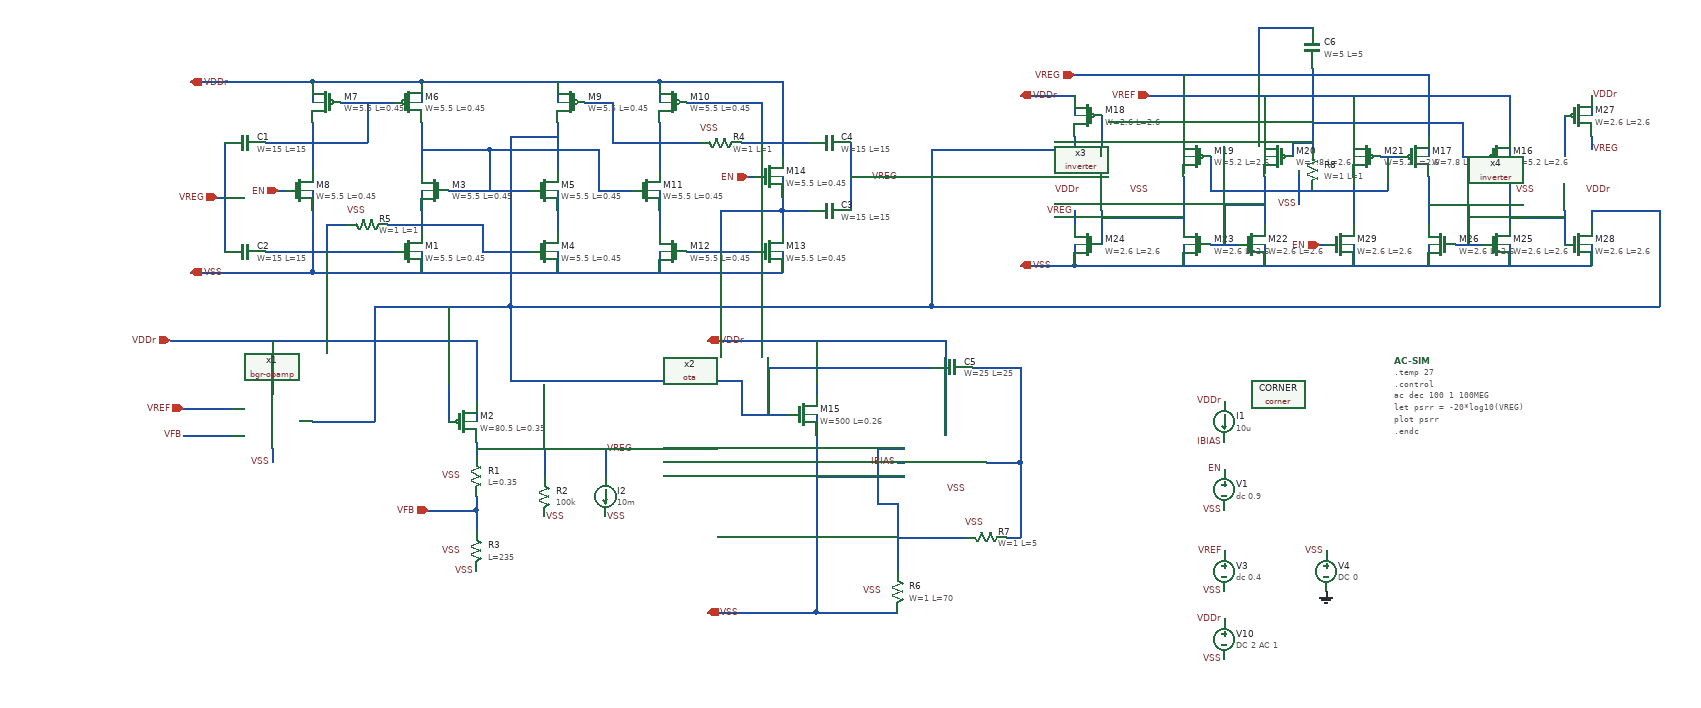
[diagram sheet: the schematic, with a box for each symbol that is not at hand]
v {xschem version=3.4.7 file_version=1.2}
G {}
K {}
V {}
S {}
E {}
N 230 -500 650 -500 {lab=VDDr}
N 650 -350 650 -330 {lab=VREG}
N 650 -440 650 -410 {lab=VDDr}
N 650 -460 650 -440 {lab=VDDr}
N 650 -410 650 -380 {lab=VDDr}
N 780 -340 840 -340 {lab=VREG}
N 650 -340 780 -340 {lab=VREG}
N 840 -340 840 -320 {lab=VREG}
N 840 -320 840 -300 {lab=VREG}
N 650 -250 650 -230 {lab=VFB}
N 580 -250 650 -250 {lab=VFB}
N 650 -270 650 -250 {lab=VFB}
N 650 -230 650 -220 {lab=VFB}
N 650 -500 650 -460 {lab=VDDr}
N 350 -460 350 -420 {lab=VDDr}
N 200 -500 230 -500 {lab=VDDr}
N 220 -400 290 -400 {lab=VREF}
N 220 -360 290 -360 {lab=VFB}
N 350 -340 350 -320 {lab=VSS}
N 350 -500 350 -460 {lab=VDDr}
N 750 -340 750 -300 {lab=VREG}
N 410 -880 570 -880 {lab=VDDr}
N 570 -880 570 -850 {lab=VDDr}
N 410 -880 410 -850 {lab=VDDr}
N 450 -850 530 -850 {lab=#net1}
N 570 -820 570 -750 {lab=#net2}
N 610 -720 730 -720 {lab=#net2}
N 570 -690 570 -660 {lab=#net3}
N 770 -690 770 -660 {lab=#net4}
N 660 -630 730 -630 {lab=#net3}
N 660 -670 660 -630 {lab=#net3}
N 570 -670 660 -670 {lab=#net3}
N 770 -630 770 -600 {lab=VSS}
N 570 -630 570 -600 {lab=VSS}
N 570 -780 670 -780 {lab=#net2}
N 670 -780 670 -720 {lab=#net2}
N 410 -820 410 -750 {lab=#net1}
N 410 -720 410 -690 {lab=VSS}
N 340 -630 530 -630 {lab=#net5}
N 340 -790 410 -790 {lab=#net1}
N 490 -850 490 -790 {lab=#net1}
N 410 -790 490 -790 {lab=#net1}
N 410 -690 410 -610 {lab=VSS}
N 410 -610 410 -600 {lab=VSS}
N 280 -790 280 -630 {lab=VREG}
N 770 -820 770 -750 {lab=#net6}
N 570 -720 570 -690 {lab=#net3}
N 770 -720 770 -690 {lab=#net4}
N 670 -780 830 -780 {lab=#net2}
N 830 -780 830 -720 {lab=#net2}
N 830 -720 880 -720 {lab=#net2}
N 920 -820 920 -750 {lab=#net7}
N 920 -880 920 -850 {lab=VDDr}
N 770 -880 770 -850 {lab=VDDr}
N 570 -880 920 -880 {lab=VDDr}
N 920 -720 920 -690 {lab=#net8}
N 960 -630 1060 -630 {lab=#net9}
N 920 -690 920 -660 {lab=#net8}
N 920 -630 920 -600 {lab=VSS}
N 1100 -630 1100 -600 {lab=VSS}
N 810 -850 850 -850 {lab=#net7}
N 850 -850 850 -790 {lab=#net7}
N 850 -790 920 -790 {lab=#net7}
N 930 -790 980 -790 {lab=#net7}
N 920 -790 930 -790 {lab=#net7}
N 920 -880 1100 -880 {lab=VDDr}
N 1010 -690 1010 -630 {lab=#net9}
N 1010 -690 1100 -690 {lab=#net9}
N 1100 -690 1140 -690 {lab=#net9}
N 1040 -790 1140 -790 {lab=VDDr}
N 1200 -790 1200 -690 {lab=VREG}
N 410 -600 1100 -600 {lab=VSS}
N 230 -600 410 -600 {lab=VSS}
N 230 -880 410 -880 {lab=VDDr}
N 960 -850 1070 -850 {lab=VDDr}
N 1070 -850 1070 -790 {lab=VDDr}
N 360 -720 370 -720 {lab=EN}
N 430 -670 460 -670 {lab=#net5}
N 430 -670 430 -630 {lab=#net5}
N 520 -670 570 -670 {lab=#net3}
N 270 -710 280 -710 {lab=VREG}
N 1200 -740 1210 -740 {lab=VREG}
N 1210 -740 1230 -740 {lab=VREG}
N 730 -800 770 -800 {lab=#net6}
N 1100 -740 1100 -710 {lab=#net9}
N 1050 -740 1060 -740 {lab=EN}
N 1100 -710 1100 -690 {lab=#net9}
N 1100 -690 1100 -660 {lab=#net9}
N 1100 -790 1100 -770 {lab=VDDr}
N 1100 -880 1100 -790 {lab=VDDr}
N 610 -550 610 -380 {lab=#net6}
N 500 -550 700 -550 {lab=#net6}
N 700 -800 700 -550 {lab=#net6}
N 700 -800 730 -800 {lab=#net6}
N 410 -380 500 -380 {lab=#net6}
N 500 -550 500 -380 {lab=#net6}
N 1270 -210 1370 -210 {lab=#net10}
N 1150 -360 1150 -100 {lab=VSS}
N 1150 -100 1270 -100 {lab=VSS}
N 1410 -320 1450 -320 {lab=#net11}
N 1450 -320 1450 -210 {lab=#net11}
N 1430 -210 1450 -210 {lab=#net11}
N 1380 -460 1450 -460 {lab=#net11}
N 1450 -460 1450 -320 {lab=#net11}
N 1040 -390 1110 -390 {lab=#net6}
N 1080 -460 1320 -460 {lab=#net6}
N 1080 -460 1080 -390 {lab=#net6}
N 1150 -500 1150 -420 {lab=VDDr}
N 1150 -390 1150 -360 {lab=VSS}
N 990 -500 1310 -500 {lab=VDDr}
N 990 -100 1150 -100 {lab=VSS}
N 1310 -500 1340 -500 {lab=VDDr}
N 1340 -500 1340 -360 {lab=VDDr}
N 1400 -320 1410 -320 {lab=#net11}
N 1270 -320 1280 -320 {lab=IBIAS}
N 1040 -440 1040 -390 {lab=#net6}
N 700 -550 700 -440 {lab=#net6}
N 700 -440 1040 -440 {lab=#net6}
N 1810 -860 1810 -800 {lab=VREF}
N 1940 -860 1940 -800 {lab=VREF}
N 2170 -860 2170 -800 {lab=VREF}
N 1780 -860 2170 -860 {lab=VREF}
N 1690 -890 1690 -800 {lab=VREG}
N 2050 -890 2050 -800 {lab=VREG}
N 1530 -890 2050 -890 {lab=VREG}
N 1690 -740 1690 -670 {lab=#net12}
N 1810 -740 1810 -670 {lab=#net13}
N 1730 -640 1770 -640 {lab=#net13}
N 1750 -700 1750 -640 {lab=#net13}
N 1750 -700 1810 -700 {lab=#net13}
N 1980 -770 2010 -770 {lab=#net14}
N 2090 -640 2130 -640 {lab=#net15}
N 2050 -740 2050 -670 {lab=#net15}
N 2170 -740 2170 -670 {lab=#net16}
N 2050 -700 2110 -700 {lab=#net15}
N 2110 -700 2110 -640 {lab=#net15}
N 1540 -610 2290 -610 {lab=VSS}
N 1530 -610 1540 -610 {lab=VSS}
N 1570 -690 1570 -670 {lab=#net12}
N 1570 -680 1690 -680 {lab=#net12}
N 1570 -780 1570 -770 {lab=#net17}
N 1530 -860 1530 -830 {lab=VDDr}
N 1530 -640 1530 -610 {lab=VSS}
N 1570 -670 1570 -640 {lab=#net12}
N 1530 -800 1530 -780 {lab=#net6}
N 1530 -690 1530 -670 {lab=VREG}
N 1570 -830 1570 -780 {lab=#net17}
N 1640 -860 1780 -860 {lab=VREF}
N 2250 -690 2250 -670 {lab=#net16}
N 2250 -780 2250 -770 {lab=#net18}
N 2290 -860 2290 -830 {lab=VDDr}
N 2290 -640 2290 -610 {lab=VSS}
N 2250 -670 2250 -640 {lab=#net16}
N 2290 -800 2290 -780 {lab=VREG}
N 2290 -690 2290 -670 {lab=#net6}
N 2250 -830 2250 -780 {lab=#net18}
N 2170 -680 2250 -680 {lab=#net16}
N 1450 -860 1530 -860 {lab=VDDr}
N 1450 -610 1530 -610 {lab=VSS}
N 1690 -800 1690 -770 {lab=VREG}
N 1810 -800 1810 -770 {lab=VREF}
N 1940 -800 1940 -770 {lab=VREF}
N 2050 -800 2050 -770 {lab=VREG}
N 2170 -800 2170 -770 {lab=VREF}
N 1810 -640 1810 -610 {lab=VSS}
N 1690 -640 1690 -610 {lab=VSS}
N 2170 -640 2170 -610 {lab=VSS}
N 1940 -740 1940 -670 {lab=#net14}
N 1990 -770 1990 -720 {lab=#net14}
N 1940 -720 1990 -720 {lab=#net14}
N 1730 -770 1730 -720 {lab=#net14}
N 1730 -720 1940 -720 {lab=#net14}
N 1880 -840 1880 -780 {lab=#net19}
N 1850 -790 1850 -770 {lab=#net19}
N 1850 -790 1880 -790 {lab=#net19}
N 2100 -770 2130 -770 {lab=#net19}
N 2100 -820 2100 -770 {lab=#net19}
N 1880 -820 2100 -820 {lab=#net19}
N 1880 -900 1880 -840 {lab=#net19}
N 1800 -960 1880 -960 {lab=VREG}
N 1800 -960 1800 -890 {lab=VREG}
N 1860 -750 1860 -700 {lab=VSS}
N 1940 -640 1940 -610 {lab=VSS}
N 2050 -640 2050 -610 {lab=VSS}
N 1890 -640 1900 -640 {lab=EN}
N 1320 -780 1530 -780 {lab=#net6}
N 1320 -780 1320 -550 {lab=#net6}
N 700 -550 1320 -550 {lab=#net6}
N 1320 -550 2390 -550 {lab=#net6}
N 2390 -690 2390 -550 {lab=#net6}
N 2290 -690 2390 -690 {lab=#net6}
N 1240 -340 1280 -340 {lab=#net10}
N 1240 -340 1240 -260 {lab=#net10}
N 1240 -260 1270 -260 {lab=#net10}
N 1270 -260 1270 -160 {lab=#net10}
N 1150 -300 1280 -300 {lab=VSS}
C {code_shown.sym} 2000 -470 0 0 {name="AC-SIM" only_toplevel=false value="

.temp 27
.control

ac dec 100 1 100MEG
let psrr = -20*log10(VREG)


plot psrr

.endc
"}
C {sky130_fd_pr/pfet_01v8.sym} 630 -380 0 0 {name=M2
W=80.5
L=0.35
nf=40
mult=100
ad="'int((nf+1)/2) * W/nf * 0.29'" 
pd="'2*int((nf+1)/2) * (W/nf + 0.29)'"
as="'int((nf+2)/2) * W/nf * 0.29'" 
ps="'2*int((nf+2)/2) * (W/nf + 0.29)'"
nrd="'0.29 / W'" nrs="'0.29 / W'"
sa=0 sb=0 sd=0
model=pfet_01v8
spiceprefix=X
}
C {lab_pin.sym} 630 -300 0 0 {name=p13 sig_type=std_logic lab=VSS}
C {lab_pin.sym} 220 -360 0 0 {name=p16 lab=VFB}
C {lab_pin.sym} 350 -320 0 0 {name=p18 sig_type=std_logic lab=VSS}
C {ipin.sym} 200 -500 0 0 {name=p25 lab=VDDr}
C {ipin.sym} 220 -400 0 0 {name=p28 lab=VREF}
C {isource.sym} 840 -270 0 0 {name=I2 value="10m"}
C {lab_pin.sym} 840 -240 0 1 {name=p29 sig_type=std_logic lab=VSS}
C {lab_pin.sym} 840 -340 0 1 {name=p32 sig_type=std_logic lab=VREG}
C {ipin.sym} 580 -250 0 0 {name=p11 lab=VFB}
C {lab_pin.sym} 630 -190 0 0 {name=p1 sig_type=std_logic lab=VSS}
C {lab_pin.sym} 650 -160 0 0 {name=p2 sig_type=std_logic lab=VSS}
C {sky130_fd_pr/res_high_po_0p35.sym} 650 -190 0 0 {name=R3
L=235
model=res_high_po_0p35
spiceprefix=X
mult=1}
C {sky130_fd_pr/res_high_po_2p85.sym} 650 -300 0 0 {name=R1
L=0.35
model=res_high_po_2p85
spiceprefix=X
mult=1}
C {vsource.sym} 1750 -160 0 0 {name=V3 value="dc 0.4" savecurrent=false}
C {lab_pin.sym} 1750 -130 0 0 {name=p9 sig_type=std_logic lab=VSS}
C {lab_pin.sym} 1750 -190 0 0 {name=p12 sig_type=std_logic lab=VREF}
C {vsource.sym} 1900 -160 0 0 {name=V4 value="DC 0" savecurrent=false}
C {gnd.sym} 1900 -130 0 0 {name=l2 lab=GND}
C {lab_pin.sym} 1900 -190 0 0 {name=p14 sig_type=std_logic lab=VSS}
C {sky130_fd_pr/corner.sym} 1830 -420 0 0 {name=CORNER only_toplevel=true corner=ss}
C {vsource.sym} 1750 -60 0 0 {name=V10 value="DC 2 AC 1" savecurrent=false}
C {lab_pin.sym} 1750 -30 0 0 {name=p30 sig_type=std_logic lab=VSS}
C {lab_pin.sym} 1750 -90 0 0 {name=p31 sig_type=std_logic lab=VDDr}
C {res.sym} 750 -270 0 0 {name=R2
value=100k
footprint=1206
device=resistor
m=1}
C {lab_pin.sym} 750 -240 0 1 {name=p4 sig_type=std_logic lab=VSS}
C {afe-icdec-teknofest-2026/bandgap/bgr-opamp/bgr-opamp.sym} 40 -220 0 0 {name=x1}
C {sky130_fd_pr/nfet_01v8.sym} 550 -630 0 0 {name=M1
W=5.5
L=0.45
nf=1 
mult=1
ad="'int((nf+1)/2) * W/nf * 0.29'" 
pd="'2*int((nf+1)/2) * (W/nf + 0.29)'"
as="'int((nf+2)/2) * W/nf * 0.29'" 
ps="'2*int((nf+2)/2) * (W/nf + 0.29)'"
nrd="'0.29 / W'" nrs="'0.29 / W'"
sa=0 sb=0 sd=0
model=nfet_01v8
spiceprefix=X
}
C {sky130_fd_pr/nfet_01v8.sym} 590 -720 0 1 {name=M3
W=5.5
L=0.45
nf=1 
mult=1
ad="'int((nf+1)/2) * W/nf * 0.29'" 
pd="'2*int((nf+1)/2) * (W/nf + 0.29)'"
as="'int((nf+2)/2) * W/nf * 0.29'" 
ps="'2*int((nf+2)/2) * (W/nf + 0.29)'"
nrd="'0.29 / W'" nrs="'0.29 / W'"
sa=0 sb=0 sd=0
model=nfet_01v8
spiceprefix=X
}
C {sky130_fd_pr/nfet_01v8.sym} 750 -630 0 0 {name=M4
W=5.5
L=0.45
nf=1 
mult=1
ad="'int((nf+1)/2) * W/nf * 0.29'" 
pd="'2*int((nf+1)/2) * (W/nf + 0.29)'"
as="'int((nf+2)/2) * W/nf * 0.29'" 
ps="'2*int((nf+2)/2) * (W/nf + 0.29)'"
nrd="'0.29 / W'" nrs="'0.29 / W'"
sa=0 sb=0 sd=0
model=nfet_01v8
spiceprefix=X
}
C {sky130_fd_pr/nfet_01v8.sym} 750 -720 0 0 {name=M5
W=5.5
L=0.45
nf=1 
mult=1
ad="'int((nf+1)/2) * W/nf * 0.29'" 
pd="'2*int((nf+1)/2) * (W/nf + 0.29)'"
as="'int((nf+2)/2) * W/nf * 0.29'" 
ps="'2*int((nf+2)/2) * (W/nf + 0.29)'"
nrd="'0.29 / W'" nrs="'0.29 / W'"
sa=0 sb=0 sd=0
model=nfet_01v8
spiceprefix=X
}
C {sky130_fd_pr/pfet_01v8.sym} 550 -850 0 0 {name=M6
W=5.5
L=0.45
nf=1
mult=1
ad="'int((nf+1)/2) * W/nf * 0.29'" 
pd="'2*int((nf+1)/2) * (W/nf + 0.29)'"
as="'int((nf+2)/2) * W/nf * 0.29'" 
ps="'2*int((nf+2)/2) * (W/nf + 0.29)'"
nrd="'0.29 / W'" nrs="'0.29 / W'"
sa=0 sb=0 sd=0
model=pfet_01v8
spiceprefix=X
}
C {sky130_fd_pr/pfet_01v8.sym} 430 -850 0 1 {name=M7
W=5.5
L=0.45
nf=1
mult=1
ad="'int((nf+1)/2) * W/nf * 0.29'" 
pd="'2*int((nf+1)/2) * (W/nf + 0.29)'"
as="'int((nf+2)/2) * W/nf * 0.29'" 
ps="'2*int((nf+2)/2) * (W/nf + 0.29)'"
nrd="'0.29 / W'" nrs="'0.29 / W'"
sa=0 sb=0 sd=0
model=pfet_01v8
spiceprefix=X
}
C {sky130_fd_pr/nfet_01v8.sym} 390 -720 0 0 {name=M8
W=5.5
L=0.45
nf=1 
mult=1
ad="'int((nf+1)/2) * W/nf * 0.29'" 
pd="'2*int((nf+1)/2) * (W/nf + 0.29)'"
as="'int((nf+2)/2) * W/nf * 0.29'" 
ps="'2*int((nf+2)/2) * (W/nf + 0.29)'"
nrd="'0.29 / W'" nrs="'0.29 / W'"
sa=0 sb=0 sd=0
model=nfet_01v8
spiceprefix=X
}
C {sky130_fd_pr/cap_mim_m3_1.sym} 310 -790 3 0 {name=C1 model=cap_mim_m3_1 W=15 L=15 MF=4 spiceprefix=X}
C {sky130_fd_pr/cap_mim_m3_1.sym} 310 -630 3 0 {name=C2 model=cap_mim_m3_1 W=15 L=15 MF=4 spiceprefix=X}
C {sky130_fd_pr/pfet_01v8.sym} 790 -850 0 1 {name=M9
W=5.5
L=0.45
nf=1
mult=1
ad="'int((nf+1)/2) * W/nf * 0.29'" 
pd="'2*int((nf+1)/2) * (W/nf + 0.29)'"
as="'int((nf+2)/2) * W/nf * 0.29'" 
ps="'2*int((nf+2)/2) * (W/nf + 0.29)'"
nrd="'0.29 / W'" nrs="'0.29 / W'"
sa=0 sb=0 sd=0
model=pfet_01v8
spiceprefix=X
}
C {sky130_fd_pr/pfet_01v8.sym} 940 -850 0 1 {name=M10
W=5.5
L=0.45
nf=1
mult=1
ad="'int((nf+1)/2) * W/nf * 0.29'" 
pd="'2*int((nf+1)/2) * (W/nf + 0.29)'"
as="'int((nf+2)/2) * W/nf * 0.29'" 
ps="'2*int((nf+2)/2) * (W/nf + 0.29)'"
nrd="'0.29 / W'" nrs="'0.29 / W'"
sa=0 sb=0 sd=0
model=pfet_01v8
spiceprefix=X
}
C {sky130_fd_pr/nfet_01v8.sym} 900 -720 0 0 {name=M11
W=5.5
L=0.45
nf=1 
mult=1
ad="'int((nf+1)/2) * W/nf * 0.29'" 
pd="'2*int((nf+1)/2) * (W/nf + 0.29)'"
as="'int((nf+2)/2) * W/nf * 0.29'" 
ps="'2*int((nf+2)/2) * (W/nf + 0.29)'"
nrd="'0.29 / W'" nrs="'0.29 / W'"
sa=0 sb=0 sd=0
model=nfet_01v8
spiceprefix=X
}
C {sky130_fd_pr/nfet_01v8.sym} 940 -630 0 1 {name=M12
W=5.5
L=0.45
nf=1 
mult=1
ad="'int((nf+1)/2) * W/nf * 0.29'" 
pd="'2*int((nf+1)/2) * (W/nf + 0.29)'"
as="'int((nf+2)/2) * W/nf * 0.29'" 
ps="'2*int((nf+2)/2) * (W/nf + 0.29)'"
nrd="'0.29 / W'" nrs="'0.29 / W'"
sa=0 sb=0 sd=0
model=nfet_01v8
spiceprefix=X
}
C {sky130_fd_pr/nfet_01v8.sym} 1080 -630 0 0 {name=M13
W=5.5
L=0.45
nf=1 
mult=1
ad="'int((nf+1)/2) * W/nf * 0.29'" 
pd="'2*int((nf+1)/2) * (W/nf + 0.29)'"
as="'int((nf+2)/2) * W/nf * 0.29'" 
ps="'2*int((nf+2)/2) * (W/nf + 0.29)'"
nrd="'0.29 / W'" nrs="'0.29 / W'"
sa=0 sb=0 sd=0
model=nfet_01v8
spiceprefix=X
}
C {sky130_fd_pr/res_xhigh_po.sym} 1010 -790 1 0 {name=R4
W=1
L=1
model=res_xhigh_po
spiceprefix=X
mult=1}
C {sky130_fd_pr/cap_mim_m3_1.sym} 1170 -690 1 0 {name=C3 model=cap_mim_m3_1 W=15 L=15 MF=4 spiceprefix=X}
C {sky130_fd_pr/cap_mim_m3_1.sym} 1170 -790 1 0 {name=C4 model=cap_mim_m3_1 W=15 L=15 MF=4 spiceprefix=X}
C {iopin.sym} 230 -600 0 1 {name=p3 lab=VSS}
C {iopin.sym} 230 -880 0 1 {name=p5 lab=VDDr}
C {ipin.sym} 360 -720 0 0 {name=p6 lab=EN
W=5.5
L=0.45}
C {lab_pin.sym} 490 -690 0 0 {name=p7 sig_type=std_logic lab=VSS
W=5.5
L=0.45}
C {lab_pin.sym} 1010 -810 0 0 {name=p8 sig_type=std_logic lab=VSS}
C {opin.sym} 270 -710 0 1 {name=p10 lab=VREG
W=15
L=15}
C {lab_pin.sym} 1230 -740 0 1 {name=p15 sig_type=std_logic lab=VREG}
C {sky130_fd_pr/res_xhigh_po.sym} 490 -670 1 0 {name=R5
W=1
L=1
model=res_xhigh_po
spiceprefix=X
mult=1}
C {sky130_fd_pr/nfet_01v8.sym} 1080 -740 0 0 {name=M14
W=5.5
L=0.45
nf=1 
mult=1
ad="'int((nf+1)/2) * W/nf * 0.29'" 
pd="'2*int((nf+1)/2) * (W/nf + 0.29)'"
as="'int((nf+2)/2) * W/nf * 0.29'" 
ps="'2*int((nf+2)/2) * (W/nf + 0.29)'"
nrd="'0.29 / W'" nrs="'0.29 / W'"
sa=0 sb=0 sd=0
model=nfet_01v8
spiceprefix=X
}
C {ipin.sym} 1050 -740 0 0 {name=p19 lab=EN
W=5.5
L=0.45}
C {vsource.sym} 1750 -280 0 0 {name=V1 value="dc 0.9" savecurrent=false}
C {lab_pin.sym} 1750 -250 0 0 {name=p17 sig_type=std_logic lab=VSS}
C {lab_pin.sym} 1750 -310 0 0 {name=p20 sig_type=std_logic lab=EN}
C {sky130_fd_pr/res_xhigh_po.sym} 1270 -130 0 0 {name=R6
W=1
L=70
model=res_xhigh_po
spiceprefix=X
mult=1}
C {sky130_fd_pr/res_xhigh_po.sym} 1400 -210 1 0 {name=R7
W=1
L=5
model=res_xhigh_po
spiceprefix=X
mult=1}
C {lab_pin.sym} 1250 -130 0 0 {name=p21 sig_type=std_logic lab=VSS}
C {lab_pin.sym} 1400 -230 0 0 {name=p22 sig_type=std_logic lab=VSS}
C {lab_pin.sym} 1340 -280 0 1 {name=p23 sig_type=std_logic lab=VSS}
C {sky130_fd_pr/nfet_01v8.sym} 1130 -390 0 0 {name=M15
W=500
L=0.26
nf=128 
mult=1
ad="'int((nf+1)/2) * W/nf * 0.29'" 
pd="'2*int((nf+1)/2) * (W/nf + 0.29)'"
as="'int((nf+2)/2) * W/nf * 0.29'" 
ps="'2*int((nf+2)/2) * (W/nf + 0.29)'"
nrd="'0.29 / W'" nrs="'0.29 / W'"
sa=0 sb=0 sd=0
model=nfet_01v8
spiceprefix=X
}
C {sky130_fd_pr/cap_mim_m3_1.sym} 1350 -460 3 0 {name=C5 model=cap_mim_m3_1 W=25 L=25 MF=64 spiceprefix=X}
C {iopin.sym} 990 -500 0 1 {name=p24 lab=VDDr}
C {iopin.sym} 990 -100 0 1 {name=p26 lab=VSS}
C {tutor-sky/ota2/ota.sym} 1120 -140 0 0 {name=x2}
C {isource.sym} 1750 -380 0 0 {name=I1 value="10u"}
C {lab_pin.sym} 1750 -410 0 0 {name=p33 sig_type=std_logic lab=VDDr}
C {lab_pin.sym} 1750 -350 0 0 {name=p34 sig_type=std_logic lab=IBIAS}
C {lab_pin.sym} 1270 -320 0 0 {name=p35 sig_type=std_logic lab=IBIAS}
C {sky130_fd_pr/pfet_01v8.sym} 2150 -770 0 0 {name=M16
W=5.2
L=2.6
nf=1
mult=1
ad="'int((nf+1)/2) * W/nf * 0.29'" 
pd="'2*int((nf+1)/2) * (W/nf + 0.29)'"
as="'int((nf+2)/2) * W/nf * 0.29'" 
ps="'2*int((nf+2)/2) * (W/nf + 0.29)'"
nrd="'0.29 / W'" nrs="'0.29 / W'"
sa=0 sb=0 sd=0
model=pfet_01v8
spiceprefix=X
}
C {sky130_fd_pr/pfet_01v8.sym} 2030 -770 0 0 {name=M17
W=7.8
L=2.6
nf=1
mult=2
ad="'int((nf+1)/2) * W/nf * 0.29'" 
pd="'2*int((nf+1)/2) * (W/nf + 0.29)'"
as="'int((nf+2)/2) * W/nf * 0.29'" 
ps="'2*int((nf+2)/2) * (W/nf + 0.29)'"
nrd="'0.29 / W'" nrs="'0.29 / W'"
sa=0 sb=0 sd=0
model=pfet_01v8
spiceprefix=X
}
C {sky130_fd_pr/pfet_01v8.sym} 1550 -830 0 1 {name=M18
W=2.6
L=2.6
nf=1
mult=1
ad="'int((nf+1)/2) * W/nf * 0.29'" 
pd="'2*int((nf+1)/2) * (W/nf + 0.29)'"
as="'int((nf+2)/2) * W/nf * 0.29'" 
ps="'2*int((nf+2)/2) * (W/nf + 0.29)'"
nrd="'0.29 / W'" nrs="'0.29 / W'"
sa=0 sb=0 sd=0
model=pfet_01v8
spiceprefix=X
}
C {sky130_fd_pr/pfet_01v8.sym} 1710 -770 0 1 {name=M19
W=5.2
L=2.6
nf=1
mult=1
ad="'int((nf+1)/2) * W/nf * 0.29'" 
pd="'2*int((nf+1)/2) * (W/nf + 0.29)'"
as="'int((nf+2)/2) * W/nf * 0.29'" 
ps="'2*int((nf+2)/2) * (W/nf + 0.29)'"
nrd="'0.29 / W'" nrs="'0.29 / W'"
sa=0 sb=0 sd=0
model=pfet_01v8
spiceprefix=X
}
C {sky130_fd_pr/pfet_01v8.sym} 1830 -770 0 1 {name=M20
W=7.8
L=2.6
nf=1
mult=2
ad="'int((nf+1)/2) * W/nf * 0.29'" 
pd="'2*int((nf+1)/2) * (W/nf + 0.29)'"
as="'int((nf+2)/2) * W/nf * 0.29'" 
ps="'2*int((nf+2)/2) * (W/nf + 0.29)'"
nrd="'0.29 / W'" nrs="'0.29 / W'"
sa=0 sb=0 sd=0
model=pfet_01v8
spiceprefix=X
}
C {sky130_fd_pr/pfet_01v8.sym} 1960 -770 0 1 {name=M21
W=5.2
L=2.6
nf=1
mult=1
ad="'int((nf+1)/2) * W/nf * 0.29'" 
pd="'2*int((nf+1)/2) * (W/nf + 0.29)'"
as="'int((nf+2)/2) * W/nf * 0.29'" 
ps="'2*int((nf+2)/2) * (W/nf + 0.29)'"
nrd="'0.29 / W'" nrs="'0.29 / W'"
sa=0 sb=0 sd=0
model=pfet_01v8
spiceprefix=X
}
C {sky130_fd_pr/nfet_01v8.sym} 1790 -640 0 0 {name=M22
W=2.6
L=2.6
nf=1 
mult=1
ad="'int((nf+1)/2) * W/nf * 0.29'" 
pd="'2*int((nf+1)/2) * (W/nf + 0.29)'"
as="'int((nf+2)/2) * W/nf * 0.29'" 
ps="'2*int((nf+2)/2) * (W/nf + 0.29)'"
nrd="'0.29 / W'" nrs="'0.29 / W'"
sa=0 sb=0 sd=0
model=nfet_01v8
spiceprefix=X
}
C {sky130_fd_pr/nfet_01v8.sym} 1710 -640 0 1 {name=M23
W=2.6
L=2.6
nf=1 
mult=1
ad="'int((nf+1)/2) * W/nf * 0.29'" 
pd="'2*int((nf+1)/2) * (W/nf + 0.29)'"
as="'int((nf+2)/2) * W/nf * 0.29'" 
ps="'2*int((nf+2)/2) * (W/nf + 0.29)'"
nrd="'0.29 / W'" nrs="'0.29 / W'"
sa=0 sb=0 sd=0
model=nfet_01v8
spiceprefix=X
}
C {sky130_fd_pr/nfet_01v8.sym} 1550 -640 0 1 {name=M24
W=2.6
L=2.6
nf=1 
mult=1
ad="'int((nf+1)/2) * W/nf * 0.29'" 
pd="'2*int((nf+1)/2) * (W/nf + 0.29)'"
as="'int((nf+2)/2) * W/nf * 0.29'" 
ps="'2*int((nf+2)/2) * (W/nf + 0.29)'"
nrd="'0.29 / W'" nrs="'0.29 / W'"
sa=0 sb=0 sd=0
model=nfet_01v8
spiceprefix=X
}
C {sky130_fd_pr/nfet_01v8.sym} 2150 -640 0 0 {name=M25
W=2.6
L=2.6
nf=1 
mult=1
ad="'int((nf+1)/2) * W/nf * 0.29'" 
pd="'2*int((nf+1)/2) * (W/nf + 0.29)'"
as="'int((nf+2)/2) * W/nf * 0.29'" 
ps="'2*int((nf+2)/2) * (W/nf + 0.29)'"
nrd="'0.29 / W'" nrs="'0.29 / W'"
sa=0 sb=0 sd=0
model=nfet_01v8
spiceprefix=X
}
C {sky130_fd_pr/nfet_01v8.sym} 2070 -640 0 1 {name=M26
W=2.6
L=2.6
nf=1 
mult=1
ad="'int((nf+1)/2) * W/nf * 0.29'" 
pd="'2*int((nf+1)/2) * (W/nf + 0.29)'"
as="'int((nf+2)/2) * W/nf * 0.29'" 
ps="'2*int((nf+2)/2) * (W/nf + 0.29)'"
nrd="'0.29 / W'" nrs="'0.29 / W'"
sa=0 sb=0 sd=0
model=nfet_01v8
spiceprefix=X
}
C {pmic-core/ldo/libs/core_analog/voltage-damper/schematics/inverter.sym} 1740 -510 3 0 {name=x3}
C {sky130_fd_pr/pfet_01v8.sym} 2270 -830 0 0 {name=M27
W=2.6
L=2.6
nf=1
mult=1
ad="'int((nf+1)/2) * W/nf * 0.29'" 
pd="'2*int((nf+1)/2) * (W/nf + 0.29)'"
as="'int((nf+2)/2) * W/nf * 0.29'" 
ps="'2*int((nf+2)/2) * (W/nf + 0.29)'"
nrd="'0.29 / W'" nrs="'0.29 / W'"
sa=0 sb=0 sd=0
model=pfet_01v8
spiceprefix=X
}
C {sky130_fd_pr/nfet_01v8.sym} 2270 -640 0 0 {name=M28
W=2.6
L=2.6
nf=1 
mult=1
ad="'int((nf+1)/2) * W/nf * 0.29'" 
pd="'2*int((nf+1)/2) * (W/nf + 0.29)'"
as="'int((nf+2)/2) * W/nf * 0.29'" 
ps="'2*int((nf+2)/2) * (W/nf + 0.29)'"
nrd="'0.29 / W'" nrs="'0.29 / W'"
sa=0 sb=0 sd=0
model=nfet_01v8
spiceprefix=X
}
C {pmic-core/ldo/libs/core_analog/voltage-damper/schematics/inverter.sym} 2080 -510 1 1 {name=x4}
C {iopin.sym} 1450 -860 0 1 {name=p27 lab=VDDr}
C {lab_pin.sym} 2290 -860 0 1 {name=p36 sig_type=std_logic lab=VDDr}
C {iopin.sym} 1450 -610 0 1 {name=p37 lab=VSS}
C {lab_pin.sym} 2280 -720 0 1 {name=p38 sig_type=std_logic lab=VDDr}
C {lab_pin.sym} 1540 -720 0 0 {name=p39 sig_type=std_logic lab=VDDr}
C {lab_pin.sym} 1610 -720 0 1 {name=p40 lab=VSS}
C {lab_pin.sym} 2210 -720 0 0 {name=p41 lab=VSS}
C {sky130_fd_pr/nfet_01v8.sym} 1920 -640 0 0 {name=M29
W=2.6
L=2.6
nf=1 
mult=1
ad="'int((nf+1)/2) * W/nf * 0.29'" 
pd="'2*int((nf+1)/2) * (W/nf + 0.29)'"
as="'int((nf+2)/2) * W/nf * 0.29'" 
ps="'2*int((nf+2)/2) * (W/nf + 0.29)'"
nrd="'0.29 / W'" nrs="'0.29 / W'"
sa=0 sb=0 sd=0
model=nfet_01v8
spiceprefix=X
}
C {sky130_fd_pr/res_xhigh_po.sym} 1880 -750 0 0 {name=R8
W=1
L=1
model=res_xhigh_po
spiceprefix=X
mult=1}
C {sky130_fd_pr/cap_mim_m3_2.sym} 1880 -930 0 0 {name=C6 model=cap_mim_m3_2 W=5 L=5 MF=4 spiceprefix=X}
C {ipin.sym} 1640 -860 0 0 {name=p42 lab=VREF}
C {ipin.sym} 1530 -890 0 0 {name=p43 lab=VREG}
C {lab_pin.sym} 1860 -700 0 0 {name=p46 lab=VSS}
C {lab_pin.sym} 1530 -690 0 0 {name=p47 lab=VREG}
C {lab_pin.sym} 2290 -780 0 1 {name=p48 lab=VREG}
C {ipin.sym} 1890 -640 0 0 {name=p49 lab=EN}
